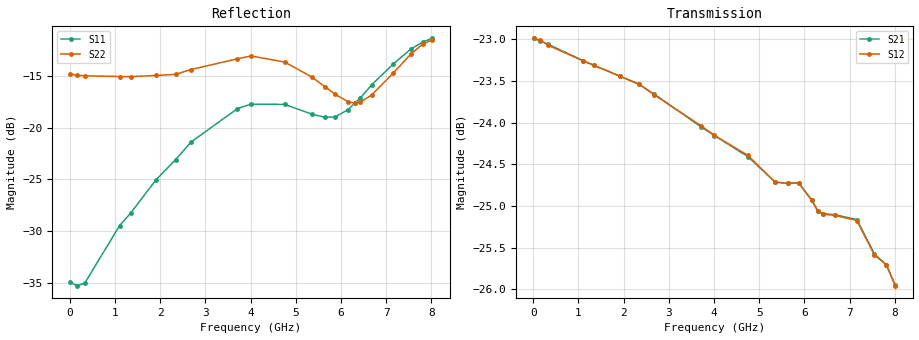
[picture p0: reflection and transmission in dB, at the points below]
! DEVICE ID: PE43712
! File Path: z:\PE43713\PE43713_CHAR_NOM_04292014\AMB\3p300\LS_ATT_21p75dB\PE43713_AMB_3p300V_3p000V_0p000V_LS_ATT_21p75dB_S2P_SN_10_A0139A.s2p
! Serial: 10
! Lot: A0139A
! Temp: 25C
! VDD: 3.300
! VSS: 0.000
! Control_Hi: 3.000
! Control_Lo: 0.000
! Attenuation Step: 21.75dB
! Port 1: RF1
! Port 2: RF2
! ThroughPath:1-2
! IDD: 0.0001471931
! ISS: -1.445e-007
#  Hz  S  RI  R  50
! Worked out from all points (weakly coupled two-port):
!   801 points, 10 MHz to 8.01 GHz, reference 50 ohm
!   highest |S21| = -22.99 dB at 10 MHz (marker M1); lowest = -25.9 dB at 8.01 GHz (marker M2)
!   lowest |S11| = -35.3 dB at 160 MHz (marker M3), VSWR 1.04, Z = 48.4 + j0.522 ohm
!   |S11| at or under -10 dB: start of sweep to end of sweep
!   |S22| runs from -17.6 to -11.5 dB; largest |S21 - S12| = 0.00026
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1e7  -0.0178 0.000673  0.0709 -0.000368  0.0709 -0.000333  -0.1819 0.00126
1.6e8  -0.0163 0.00539  0.0705 -0.00428  0.0706 -0.00427  -0.1796 0.0122
3.3e8  -0.0148 0.00966  0.0698 -0.00864  0.0697 -0.00855  -0.1772 0.0224
1.1e9  -0.00991 0.032  0.0636 -0.0261  0.0636 -0.0261  -0.1626 0.0704
1.35e9  -0.00631 0.0382  0.0608 -0.0311  0.0608 -0.0311  -0.1558 0.0839
1.91e9  0.00516 0.0558  0.0533 -0.0411  0.0533 -0.0411  -0.1348 0.1182
2.34e9  0.0167 0.068  0.0463 -0.0478  0.0463 -0.0478  -0.1152 0.1404
2.68e9  0.0272 0.0808  0.0403 -0.0518  0.0402 -0.0518  -0.0982 0.1645
3.71e9  0.0447 0.1155  0.0199 -0.0595  0.0199 -0.0596  -0.0651 0.2059
4.01e9  0.0472 0.1213  0.0139 -0.0604  0.014 -0.0604  -0.0616 0.2141
4.75e9  0.0539 0.1181  -0.000123 -0.0602  -9.5e-05 -0.0603  -0.0413 0.2043
5.35e9  0.0684 0.0944  -0.0103 -0.0572  -0.0103 -0.0572  -0.0218 0.1751
5.64e9  0.0798 0.0792  -0.0148 -0.0561  -0.0148 -0.0561  -0.0013 0.1584
5.87e9  0.0907 0.0672  -0.0192 -0.0548  -0.0192 -0.0548  0.0187 0.1441
6.16e9  0.1086 0.0567  -0.0246 -0.0511  -0.0245 -0.0511  0.0488 0.1244
6.3e9  0.1207 0.0526  -0.0258 -0.0495  -0.0258 -0.0495  0.0658 0.1142
6.42e9  0.1295 0.0502  -0.0271 -0.0486  -0.027 -0.0486  0.0797 0.1061
6.68e9  0.1548 0.0466  -0.0307 -0.0463  -0.0306 -0.0463  0.1109 0.0923
7.16e9  0.1988 0.0461  -0.0378 -0.0402  -0.0377 -0.0402  0.1641 0.0845
7.55e9  0.2355 0.0519  -0.0409 -0.0331  -0.0408 -0.0331  0.2101 0.0885
7.81e9  0.2536 0.0582  -0.0425 -0.0297  -0.0425 -0.0297  0.2366 0.0941
8.01e9  0.2637 0.0635  -0.0428 -0.0266  -0.0427 -0.0267  0.2487 0.0946
